VERSION 5.8 ;
BUSBITCHARS "[]" ;
DIVIDERCHAR "/" ;
UNITS
    DATABASE MICRONS 1000 ;
END UNITS

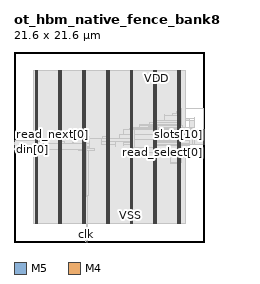
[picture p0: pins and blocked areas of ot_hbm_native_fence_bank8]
MACRO ot_hbm_native_fence_bank8
  FOREIGN ot_hbm_native_fence_bank8 0 0 ;
  CLASS BLOCK ;
  SIZE 21.6 BY 21.6 ;
  PIN clk
    DIRECTION INPUT ;
    USE SIGNAL ;
    PORT
      LAYER M5 ;
        RECT  8.208 0 8.232 0.084 ;
    END
  END clk
  PIN din[0]
    DIRECTION INPUT ;
    USE SIGNAL ;
    PORT
      LAYER M4 ;
        RECT  0 10.512 0.084 10.536 ;
    END
  END din[0]
  PIN din[1]
    DIRECTION INPUT ;
    USE SIGNAL ;
    PORT
      LAYER M4 ;
        RECT  0 10.608 0.084 10.632 ;
    END
  END din[1]
  PIN din[2]
    DIRECTION INPUT ;
    USE SIGNAL ;
    PORT
      LAYER M4 ;
        RECT  0 10.704 0.084 10.728 ;
    END
  END din[2]
  PIN din[3]
    DIRECTION INPUT ;
    USE SIGNAL ;
    PORT
      LAYER M4 ;
        RECT  0 10.8 0.084 10.824 ;
    END
  END din[3]
  PIN din[4]
    DIRECTION INPUT ;
    USE SIGNAL ;
    PORT
      LAYER M4 ;
        RECT  0 10.896 0.084 10.92 ;
    END
  END din[4]
  PIN din[5]
    DIRECTION INPUT ;
    USE SIGNAL ;
    PORT
      LAYER M4 ;
        RECT  0 10.992 0.084 11.016 ;
    END
  END din[5]
  PIN din[6]
    DIRECTION INPUT ;
    USE SIGNAL ;
    PORT
      LAYER M4 ;
        RECT  0 11.088 0.084 11.112 ;
    END
  END din[6]
  PIN din[7]
    DIRECTION INPUT ;
    USE SIGNAL ;
    PORT
      LAYER M4 ;
        RECT  0 11.184 0.084 11.208 ;
    END
  END din[7]
  PIN read_next[0]
    DIRECTION INPUT ;
    USE SIGNAL ;
    PORT
      LAYER M4 ;
        RECT  0 11.28 0.084 11.304 ;
    END
  END read_next[0]
  PIN read_next[1]
    DIRECTION INPUT ;
    USE SIGNAL ;
    PORT
      LAYER M4 ;
        RECT  0 11.376 0.084 11.4 ;
    END
  END read_next[1]
  PIN read_select[0]
    DIRECTION OUTPUT ;
    USE SIGNAL ;
    PORT
      LAYER M4 ;
        RECT  21.516 11.088 21.6 11.112 ;
    END
  END read_select[0]
  PIN read_select[1]
    DIRECTION OUTPUT ;
    USE SIGNAL ;
    PORT
      LAYER M4 ;
        RECT  21.516 11.184 21.6 11.208 ;
    END
  END read_select[1]
  PIN rst_n
    DIRECTION INPUT ;
    USE SIGNAL ;
    PORT
      LAYER M5 ;
        RECT  8.304 0 8.328 0.084 ;
    END
  END rst_n
  PIN slots[0]
    DIRECTION OUTPUT ;
    USE SIGNAL ;
    PORT
      LAYER M4 ;
        RECT  21.516 11.28 21.6 11.304 ;
    END
  END slots[0]
  PIN slots[10]
    DIRECTION OUTPUT ;
    USE SIGNAL ;
    PORT
      LAYER M4 ;
        RECT  21.516 12.24 21.6 12.264 ;
    END
  END slots[10]
  PIN slots[11]
    DIRECTION OUTPUT ;
    USE SIGNAL ;
    PORT
      LAYER M4 ;
        RECT  21.516 12.336 21.6 12.36 ;
    END
  END slots[11]
  PIN slots[12]
    DIRECTION OUTPUT ;
    USE SIGNAL ;
    PORT
      LAYER M4 ;
        RECT  21.516 12.432 21.6 12.456 ;
    END
  END slots[12]
  PIN slots[13]
    DIRECTION OUTPUT ;
    USE SIGNAL ;
    PORT
      LAYER M4 ;
        RECT  21.516 12.528 21.6 12.552 ;
    END
  END slots[13]
  PIN slots[14]
    DIRECTION OUTPUT ;
    USE SIGNAL ;
    PORT
      LAYER M4 ;
        RECT  21.516 12.624 21.6 12.648 ;
    END
  END slots[14]
  PIN slots[15]
    DIRECTION OUTPUT ;
    USE SIGNAL ;
    PORT
      LAYER M4 ;
        RECT  21.516 12.72 21.6 12.744 ;
    END
  END slots[15]
  PIN slots[1]
    DIRECTION OUTPUT ;
    USE SIGNAL ;
    PORT
      LAYER M4 ;
        RECT  21.516 11.376 21.6 11.4 ;
    END
  END slots[1]
  PIN slots[2]
    DIRECTION OUTPUT ;
    USE SIGNAL ;
    PORT
      LAYER M4 ;
        RECT  21.516 11.472 21.6 11.496 ;
    END
  END slots[2]
  PIN slots[3]
    DIRECTION OUTPUT ;
    USE SIGNAL ;
    PORT
      LAYER M4 ;
        RECT  21.516 11.568 21.6 11.592 ;
    END
  END slots[3]
  PIN slots[4]
    DIRECTION OUTPUT ;
    USE SIGNAL ;
    PORT
      LAYER M4 ;
        RECT  21.516 11.664 21.6 11.688 ;
    END
  END slots[4]
  PIN slots[5]
    DIRECTION OUTPUT ;
    USE SIGNAL ;
    PORT
      LAYER M4 ;
        RECT  21.516 11.76 21.6 11.784 ;
    END
  END slots[5]
  PIN slots[6]
    DIRECTION OUTPUT ;
    USE SIGNAL ;
    PORT
      LAYER M4 ;
        RECT  21.516 11.856 21.6 11.88 ;
    END
  END slots[6]
  PIN slots[7]
    DIRECTION OUTPUT ;
    USE SIGNAL ;
    PORT
      LAYER M4 ;
        RECT  21.516 11.952 21.6 11.976 ;
    END
  END slots[7]
  PIN slots[8]
    DIRECTION OUTPUT ;
    USE SIGNAL ;
    PORT
      LAYER M4 ;
        RECT  21.516 12.048 21.6 12.072 ;
    END
  END slots[8]
  PIN slots[9]
    DIRECTION OUTPUT ;
    USE SIGNAL ;
    PORT
      LAYER M4 ;
        RECT  21.516 12.144 21.6 12.168 ;
    END
  END slots[9]
  PIN write_next[0]
    DIRECTION INPUT ;
    USE SIGNAL ;
    PORT
      LAYER M4 ;
        RECT  0 11.472 0.084 11.496 ;
    END
  END write_next[0]
  PIN write_next[1]
    DIRECTION INPUT ;
    USE SIGNAL ;
    PORT
      LAYER M4 ;
        RECT  0 11.568 0.084 11.592 ;
    END
  END write_next[1]
  PIN VDD
    DIRECTION INOUT ;
    USE POWER ;
    PORT
      LAYER M5 ;
        RECT  18.792 2.151 18.912 19.449 ;
        RECT  16.092 2.151 16.212 19.449 ;
        RECT  13.392 2.151 13.512 19.449 ;
        RECT  10.692 2.151 10.812 19.449 ;
        RECT  7.992 2.151 8.112 19.449 ;
        RECT  5.292 2.151 5.412 19.449 ;
        RECT  2.592 2.151 2.712 19.449 ;
    END
  END VDD
  PIN VSS
    DIRECTION INOUT ;
    USE GROUND ;
    PORT
      LAYER M5 ;
        RECT  18.6 2.137 18.72 19.463 ;
        RECT  15.9 2.137 16.02 19.463 ;
        RECT  13.2 2.137 13.32 19.463 ;
        RECT  10.5 2.137 10.62 19.463 ;
        RECT  7.8 2.137 7.92 19.463 ;
        RECT  5.1 2.137 5.22 19.463 ;
        RECT  2.4 2.137 2.52 19.463 ;
    END
  END VSS
  # OT_OBS_CLOSED layer=M5 d_um=1.536 added=0
  OBS
    LAYER RVTN ;
     RECT  2.16 2.16 19.44 2.295 ;
     RECT  2.16 2.565 19.44 2.835 ;
     RECT  2.16 3.105 19.44 3.375 ;
     RECT  2.16 3.645 19.44 3.915 ;
     RECT  2.16 4.185 19.44 4.455 ;
     RECT  2.16 4.725 19.44 4.995 ;
     RECT  2.16 5.265 19.44 5.535 ;
     RECT  2.16 5.805 19.44 6.075 ;
     RECT  2.16 6.345 19.44 6.615 ;
     RECT  2.16 6.885 19.44 7.155 ;
     RECT  2.16 7.425 19.44 7.695 ;
     RECT  2.16 7.965 19.44 8.235 ;
     RECT  2.16 8.505 19.44 8.775 ;
     RECT  2.16 9.045 19.44 9.315 ;
     RECT  2.16 9.585 19.44 9.855 ;
     RECT  2.16 10.125 19.44 10.395 ;
     RECT  2.16 10.665 19.44 10.935 ;
     RECT  2.16 11.205 19.44 11.475 ;
     RECT  2.16 11.745 19.44 12.015 ;
     RECT  2.16 12.285 19.44 12.555 ;
     RECT  2.16 12.825 19.44 13.095 ;
     RECT  2.16 13.365 19.44 13.635 ;
     RECT  2.16 13.905 19.44 14.175 ;
     RECT  2.16 14.445 19.44 14.715 ;
     RECT  2.16 14.985 19.44 15.255 ;
     RECT  2.16 15.525 19.44 15.795 ;
     RECT  2.16 16.065 19.44 16.335 ;
     RECT  2.16 16.605 19.44 16.875 ;
     RECT  2.16 17.145 19.44 17.415 ;
     RECT  2.16 17.685 19.44 17.955 ;
     RECT  2.16 18.225 19.44 18.495 ;
     RECT  2.16 18.765 19.44 19.035 ;
     RECT  2.16 19.305 19.44 19.44 ;
    LAYER RVTP ;
     RECT  2.16 2.295 19.44 2.565 ;
     RECT  2.16 2.835 19.44 3.105 ;
     RECT  2.16 3.375 19.44 3.645 ;
     RECT  2.16 3.915 19.44 4.185 ;
     RECT  2.16 4.455 19.44 4.725 ;
     RECT  2.16 4.995 19.44 5.265 ;
     RECT  2.16 5.535 19.44 5.805 ;
     RECT  2.16 6.075 19.44 6.345 ;
     RECT  2.16 6.615 19.44 6.885 ;
     RECT  2.16 7.155 19.44 7.425 ;
     RECT  2.16 7.695 19.44 7.965 ;
     RECT  2.16 8.235 19.44 8.505 ;
     RECT  2.16 8.775 19.44 9.045 ;
     RECT  2.16 9.315 19.44 9.585 ;
     RECT  2.16 9.855 19.44 10.125 ;
     RECT  2.16 10.395 19.44 10.665 ;
     RECT  2.16 10.935 19.44 11.205 ;
     RECT  2.16 11.475 19.44 11.745 ;
     RECT  2.16 12.015 19.44 12.285 ;
     RECT  2.16 12.555 19.44 12.825 ;
     RECT  2.16 13.095 19.44 13.365 ;
     RECT  2.16 13.635 19.44 13.905 ;
     RECT  2.16 14.175 19.44 14.445 ;
     RECT  2.16 14.715 19.44 14.985 ;
     RECT  2.16 15.255 19.44 15.525 ;
     RECT  2.16 15.795 19.44 16.065 ;
     RECT  2.16 16.335 19.44 16.605 ;
     RECT  2.16 16.875 19.44 17.145 ;
     RECT  2.16 17.415 19.44 17.685 ;
     RECT  2.16 17.955 19.44 18.225 ;
     RECT  2.16 18.495 19.44 18.765 ;
     RECT  2.16 19.035 19.44 19.305 ;
    LAYER M1 ;
     RECT  2.16 2.151 19.44 19.449 ;
    LAYER M2 ;
     RECT  0.103 11.52 0.139 11.538 ;
     RECT  0.139 11.484 2.16 11.538 ;
     RECT  2.16 2.151 19.44 19.449 ;
     RECT  19.44 13.806 19.931 14.094 ;
     RECT  19.44 9.828 19.967 9.846 ;
     RECT  19.44 11.286 20.291 12.888 ;
     RECT  20.291 11.286 20.435 12.744 ;
     RECT  20.435 11.286 20.507 12.474 ;
     RECT  19.931 14.076 20.507 14.094 ;
     RECT  20.507 11.376 21.515 11.394 ;
     RECT  19.44 15.156 21.515 15.174 ;
    LAYER M3 ;
     RECT  8.316 0.139 8.334 0.365 ;
     RECT  2.415 2.143 2.505 2.413 ;
     RECT  5.115 2.143 5.205 2.413 ;
     RECT  7.815 2.143 7.905 2.413 ;
     RECT  10.515 2.143 10.605 2.413 ;
     RECT  13.215 2.143 13.305 2.413 ;
     RECT  15.915 2.143 16.005 2.413 ;
     RECT  18.615 2.143 18.705 2.413 ;
     RECT  7.815 2.413 8.097 5.131 ;
     RECT  7.815 5.131 8.298 5.341 ;
     RECT  18.615 2.413 18.897 8.941 ;
     RECT  17.82 8.941 18.897 9.085 ;
     RECT  17.82 9.085 19.098 9.661 ;
     RECT  17.676 9.661 19.386 9.751 ;
     RECT  17.388 9.751 19.386 9.787 ;
     RECT  17.172 9.787 19.386 9.823 ;
     RECT  13.215 2.413 13.497 9.931 ;
     RECT  13.215 9.931 14.202 10.049 ;
     RECT  15.012 9.823 15.03 10.057 ;
     RECT  15.915 2.413 16.197 10.093 ;
     RECT  17.172 9.823 19.962 10.093 ;
     RECT  14.976 10.057 15.03 10.165 ;
     RECT  15.915 10.093 19.962 10.165 ;
     RECT  7.815 5.341 8.514 10.363 ;
     RECT  2.415 2.413 2.697 10.459 ;
     RECT  5.115 2.413 5.397 10.459 ;
     RECT  7.308 10.363 9.162 10.589 ;
     RECT  7.308 10.589 8.586 10.597 ;
     RECT  6.264 10.651 6.282 10.699 ;
     RECT  7.092 10.597 8.586 10.699 ;
     RECT  5.115 10.459 5.49 10.891 ;
     RECT  6.264 10.699 8.586 10.891 ;
     RECT  14.832 10.165 19.962 10.975 ;
     RECT  0.144 10.651 0.162 10.987 ;
     RECT  13.215 10.049 13.878 11.011 ;
     RECT  14.724 10.975 19.962 11.011 ;
     RECT  10.515 2.413 10.797 11.101 ;
     RECT  11.52 10.831 11.538 11.101 ;
     RECT  12.42 11.011 12.438 11.101 ;
     RECT  13.215 11.011 19.962 11.101 ;
     RECT  2.415 10.459 2.79 11.137 ;
     RECT  10.515 11.101 11.538 11.137 ;
     RECT  5.115 10.891 8.586 11.165 ;
     RECT  2.415 11.137 2.934 11.173 ;
     RECT  6.696 11.165 8.586 11.213 ;
     RECT  6.696 11.213 6.858 11.237 ;
     RECT  7.776 11.213 8.586 11.237 ;
     RECT  2.415 11.173 3.654 11.245 ;
     RECT  12.42 11.101 19.962 11.272 ;
     RECT  9.972 11.137 11.538 11.371 ;
     RECT  12.42 11.272 20.502 11.371 ;
     RECT  2.304 11.245 3.978 11.399 ;
     RECT  2.304 11.399 3.654 11.435 ;
     RECT  5.115 11.165 5.706 11.435 ;
     RECT  0.108 10.987 0.162 11.507 ;
     RECT  0.108 11.507 0.126 11.543 ;
     RECT  7.776 11.237 8.55 11.543 ;
     RECT  6.696 11.237 6.714 11.579 ;
     RECT  9.972 11.371 20.502 11.579 ;
     RECT  21.492 11.371 21.51 11.693 ;
     RECT  9.972 11.579 10.797 11.705 ;
     RECT  10.116 11.705 10.797 11.939 ;
     RECT  2.304 11.435 2.934 11.975 ;
     RECT  7.815 11.543 8.55 11.975 ;
     RECT  11.988 11.579 20.502 12.245 ;
     RECT  12.42 12.245 20.502 12.797 ;
     RECT  13.14 12.797 20.502 12.893 ;
     RECT  13.215 12.893 20.502 13.019 ;
     RECT  13.215 13.019 19.134 13.055 ;
     RECT  14.292 13.055 19.134 13.289 ;
     RECT  14.292 13.289 19.098 13.325 ;
     RECT  15.192 13.325 19.098 13.397 ;
     RECT  15.444 13.397 19.098 13.595 ;
     RECT  19.908 13.019 20.502 13.829 ;
     RECT  15.915 13.595 19.098 13.865 ;
     RECT  20.484 13.829 20.502 14.099 ;
     RECT  17.1 13.865 19.098 14.369 ;
     RECT  17.1 14.369 17.118 14.549 ;
     RECT  18.072 14.369 19.098 14.639 ;
     RECT  18.468 14.639 19.098 14.819 ;
     RECT  21.492 12.619 21.51 15.179 ;
     RECT  18.615 14.819 19.098 15.215 ;
     RECT  2.415 11.975 2.697 19.187 ;
     RECT  5.115 11.435 5.397 19.187 ;
     RECT  7.815 11.975 8.097 19.187 ;
     RECT  10.515 11.939 10.797 19.187 ;
     RECT  13.215 13.055 13.497 19.187 ;
     RECT  15.915 13.865 16.197 19.187 ;
     RECT  18.615 15.215 18.897 19.187 ;
     RECT  2.415 19.187 2.505 19.457 ;
     RECT  5.115 19.187 5.205 19.457 ;
     RECT  7.815 19.187 7.905 19.457 ;
     RECT  10.515 19.187 10.605 19.457 ;
     RECT  13.215 19.187 13.305 19.457 ;
     RECT  15.915 19.187 16.005 19.457 ;
     RECT  18.615 19.187 18.705 19.457 ;
    LAYER M4 ;
     RECT  0.06 10.512 2.408 11.592 ;
     RECT  2.408 2.148 2.512 19.452 ;
     RECT  2.512 2.418 2.704 19.182 ;
     RECT  2.704 10.464 5.108 11.208 ;
     RECT  5.108 2.148 5.212 19.452 ;
     RECT  5.212 2.418 5.404 19.182 ;
     RECT  5.404 10.464 7.808 11.208 ;
     RECT  7.808 2.148 7.912 19.452 ;
     RECT  7.912 2.418 8.104 19.182 ;
     RECT  8.101 0.096 8.243 0.264 ;
     RECT  8.243 0.144 8.3 0.264 ;
     RECT  8.3 0.144 8.38 0.36 ;
     RECT  8.38 0.336 8.387 0.36 ;
     RECT  8.104 5.136 8.387 5.16 ;
     RECT  8.104 11.712 9.961 11.736 ;
     RECT  9.961 11.424 10.508 11.736 ;
     RECT  10.508 2.148 10.612 19.452 ;
     RECT  10.612 2.418 10.804 19.182 ;
     RECT  10.804 11.424 13.208 11.736 ;
     RECT  12.409 12.768 13.208 12.792 ;
     RECT  13.208 2.148 13.312 19.452 ;
     RECT  13.312 2.418 13.504 19.182 ;
     RECT  13.504 10.704 13.667 12.792 ;
     RECT  13.667 12.768 14.105 12.792 ;
     RECT  13.667 10.704 15.908 11.688 ;
     RECT  15.325 13.056 15.908 13.08 ;
     RECT  15.908 2.148 16.012 19.452 ;
     RECT  16.012 2.418 16.204 19.182 ;
     RECT  16.204 13.056 16.337 13.08 ;
     RECT  16.204 10.992 17.057 11.016 ;
     RECT  17.197 10.08 18.608 10.104 ;
     RECT  18.608 2.148 18.712 19.452 ;
     RECT  18.712 2.418 18.904 19.182 ;
     RECT  18.904 11.184 19.897 11.496 ;
     RECT  19.897 11.184 19.933 12.456 ;
     RECT  19.933 11.088 20.257 12.456 ;
     RECT  20.257 11.088 20.473 12.552 ;
     RECT  20.473 11.088 21.564 12.744 ;
    LAYER M5 ;
     RECT  8.208 0.016 8.328 0.085 ;
     RECT  8.112 0.085 8.328 0.275 ;
     RECT  8.256 0.275 8.328 0.325 ;
     RECT  8.256 0.325 8.376 2.137 ;
     RECT  2.4 2.137 2.52 2.151 ;
     RECT  5.1 2.137 5.22 2.151 ;
     RECT  10.5 2.137 10.62 2.151 ;
     RECT  13.2 2.137 13.32 2.151 ;
     RECT  15.9 2.137 16.02 2.151 ;
     RECT  18.6 2.137 18.72 2.151 ;
     RECT  7.8 2.137 8.376 5.171 ;
     RECT  13.2 2.151 13.512 10.789 ;
     RECT  7.8 5.171 8.28 11.747 ;
     RECT  13.2 10.789 13.656 12.803 ;
     RECT  2.4 2.151 2.712 19.449 ;
     RECT  5.1 2.151 5.412 19.449 ;
     RECT  7.8 11.747 8.112 19.449 ;
     RECT  10.5 2.151 10.812 19.449 ;
     RECT  13.2 12.803 13.512 19.449 ;
     RECT  15.9 2.151 16.212 19.449 ;
     RECT  18.6 2.151 18.912 19.449 ;
     RECT  2.4 19.449 2.52 19.463 ;
     RECT  5.1 19.449 5.22 19.463 ;
     RECT  7.8 19.449 7.92 19.463 ;
     RECT  10.5 19.449 10.62 19.463 ;
     RECT  13.2 19.449 13.32 19.463 ;
     RECT  15.9 19.449 16.02 19.463 ;
     RECT  18.6 19.449 18.72 19.463 ;
  END
END ot_hbm_native_fence_bank8
END LIBRARY
